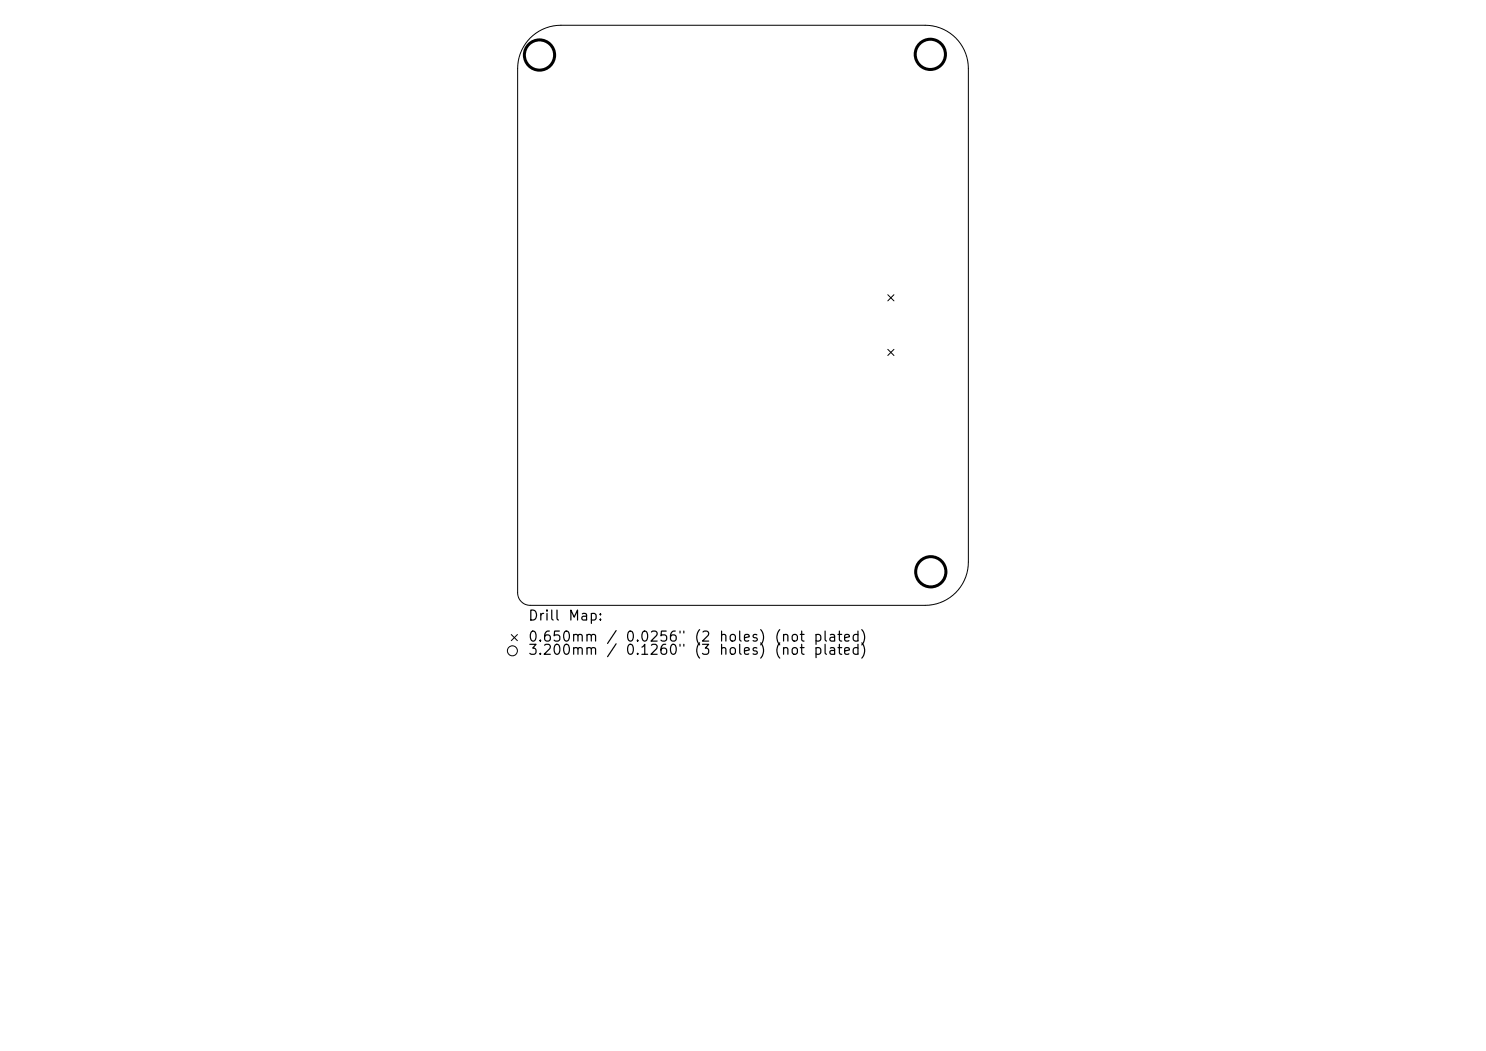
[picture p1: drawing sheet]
<svg xmlns="http://www.w3.org/2000/svg" width="297mm" height="210mm" viewBox="0 0 297 210" stroke-linecap="round" stroke-linejoin="round" font-family="sans-serif">
<defs><g id="words">
<g font-size="2">
<text x="105.4" y="124.5">Drill</text>
<text x="113.4" y="124.5">Map:</text>
<text x="105.4" y="128.7">0.650mm</text>
<text x="105.4" y="131.3">3.200mm</text>
<text x="121" y="128.7">/</text>
<text x="121" y="131.3">/</text>
<text x="124.9" y="128.7">0.0256&quot;</text>
<text x="124.9" y="131.3">0.1260&quot;</text>
<text x="138.6" y="128.7">(2</text>
<text x="138.6" y="131.3">(3</text>
<text x="143.5" y="128.7">holes)</text>
<text x="143.5" y="131.3">holes)</text>
<text x="154.6" y="128.7">(not</text>
<text x="154.6" y="131.3">(not</text>
<text x="162.4" y="128.7">plated)</text>
<text x="162.4" y="131.3">plated)</text>
</g>
</g></defs>
<g fill="none" stroke="#000" stroke-width=".2">
<path d="M106 7.6a8.6 8.6 0 0 1 6.1-2.6h72.8a8.6 8.6 0 0 1 8.6 8.7v98.6a8.6 8.6 0 0 1-8.6 8.7h-78.9a2.5 2.5 0 0 1-2.5-2.5v-104.8a8.6 8.6 0 0 1 2.5-6.1zM177.4 58.9l1.3 1.2M178.7 58.9l-1.3 1.2M177.4 69.8l1.3 1.2M178.7 69.8l-1.3 1.2M102.2 126.8l1.2 1.2M103.4 126.8l-1.2 1.2"/>
<circle cx="102.4" cy="130" r="1"/>
</g>
<g fill="none" stroke="#000" stroke-width=".6">
<circle cx="107.8" cy="11" r="3"/>
<circle cx="185.9" cy="10.9" r="3"/>
<circle cx="186" cy="114.3" r="3"/>
</g>
<use href="#words"/>
</svg>
